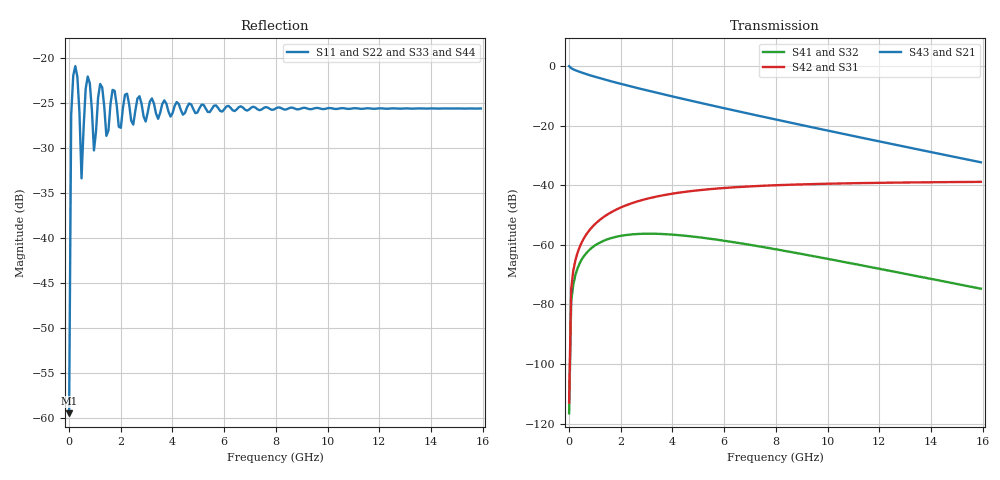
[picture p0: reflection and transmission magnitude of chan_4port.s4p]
! Created with skrf 2.1.0 (http://scikit-rf.org).
# Hz S MA R 50.0
!freq magS11 angS11 magS12 angS12 magS13 angS13
! magS14 angS14
! magS21 angS21 magS22 angS22 magS23 angS23
! magS24 angS24
! magS31 angS31 magS32 angS32 magS33 angS33
! magS34 angS34
! magS41 angS41 magS42 angS42 magS43 angS43
! magS44 angS44
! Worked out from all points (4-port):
!   200 points, 1 MHz to 15.93 GHz, reference 50 ohm
!   strongest paths, dB at 1 MHz, 4.004 GHz, 8.007 GHz, 12.01 GHz, 15.93 GHz:
!     S43: -0.1, -10.2, -18.0, -25.3, -32.3
!     S21: -0.1, -10.2, -18.0, -25.3, -32.3
!     S42: -112.9, -42.8, -40.0, -39.2, -38.9
!     S31: -112.9, -42.8, -40.0, -39.2, -38.9
!     S41: -116.5, -56.6, -61.5, -68.0, -74.7
!     S32: -116.5, -56.6, -61.5, -68.0, -74.7
!   lowest |S11| = -59.5 dB at 1 MHz (marker M1), VSWR 1.00, Z = 49.9 - j0.0663 ohm
!   |S11| at or under -10 dB: start of sweep to end of sweep
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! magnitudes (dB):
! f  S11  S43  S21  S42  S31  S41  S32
! 1 MHz  -59.5  -0.1  -0.1  -112.9  -112.9  -116.5  -116.5
! 81.06 MHz  -26.3  -0.7  -0.7  -74.7  -74.7  -79.0  -79.0
! 241.2 MHz  -20.9  -1.4  -1.4  -65.3  -65.3  -70.2  -70.2
! 481.4 MHz  -33.4  -2.2  -2.2  -59.3  -59.3  -65.0  -65.0
! 721.6 MHz  -22.0  -2.9  -2.9  -55.8  -55.8  -62.2  -62.2
! 3.524 GHz  -26.1  -9.3  -9.3  -43.6  -43.6  -56.3  -56.3
! 15.93 GHz  -25.6  -32.3  -32.3  -38.9  -38.9  -74.7  -74.7
